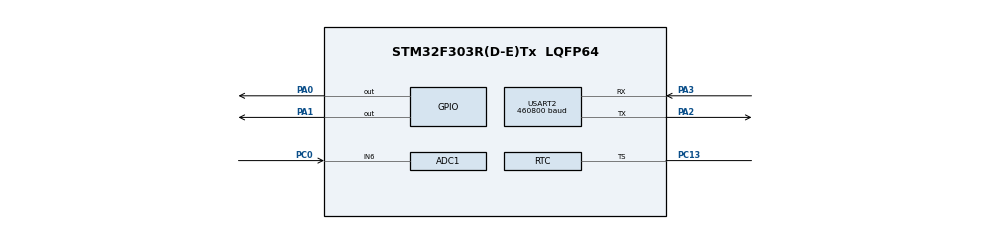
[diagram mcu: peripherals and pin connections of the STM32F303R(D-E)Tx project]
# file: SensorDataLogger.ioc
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ADC1.Channel-0\#ChannelRegularConversion=ADC_CHANNEL_6
ADC1.ClockPrescaler=ADC_CLOCK_SYNC_PCLK_DIV1
ADC1.NbrOfConversionFlag=1
ADC1.Offset-0\#ChannelRegularConversion=0
ADC1.OffsetNumber-0\#ChannelRegularConversion=ADC_OFFSET_NONE
ADC1.Rank-0\#ChannelRegularConversion=1
ADC1.SamplingTime-0\#ChannelRegularConversion=ADC_SAMPLETIME_1CYCLE_5
ADC1.master=1
FREERTOS.Tasks01=readDHT11Data,24,128,StartDefaultTask,Default,NULL,Dynamic,NULL,NULL;PotentiometerDa,24,128,readPotentiometerData,Default,NULL,Dynamic,NULL,NULL
Mcu.Family=STM32F3
Mcu.Name=STM32F303R(D-E)Tx
Mcu.Package=LQFP64
NVIC.PriorityGroup=NVIC_PRIORITYGROUP_4
NVIC.TIM1_UP_TIM16_IRQn=true\:0\:0\:false\:false\:true\:false\:false\:true
NVIC.TimeBase=TIM1_UP_TIM16_IRQn
NVIC.TimeBaseIP=TIM1
PA0.Signal=GPIO_Output
PA1.Signal=GPIO_Output
PA13.Mode=Serial_Wire
PA13.Signal=SYS_JTMS-SWDIO
PA14.Mode=Serial_Wire
PA14.Signal=SYS_JTCK-SWCLK
PA2.Mode=Asynchronous
PA2.Signal=USART2_TX
PA3.Mode=Asynchronous
PA3.Signal=USART2_RX
PC0.Signal=ADCx_IN6
PC13.Mode=Timestamp enabled
PC13.Signal=RTC_TS
PF0-OSC_IN.Mode=HSE-External-Oscillator
PF0-OSC_IN.Signal=RCC_OSC_IN
PF1-OSC_OUT.Mode=HSE-External-Oscillator
PF1-OSC_OUT.Signal=RCC_OSC_OUT
ProjectManager.HeapSize=0x200
ProjectManager.StackSize=0x400
ProjectManager.TargetToolchain=STM32CubeIDE
RCC.AHBFreq_Value=72000000
RCC.APB1CLKDivider=RCC_HCLK_DIV2
RCC.APB1Freq_Value=36000000
RCC.APB1TimFreq_Value=72000000
RCC.APB2Freq_Value=72000000
RCC.APB2TimFreq_Value=72000000
RCC.CortexFreq_Value=72000000
RCC.HCLKFreq_Value=72000000
RCC.HSE_VALUE=8000000
RCC.HSI_VALUE=8000000
RCC.LSE_VALUE=32768
RCC.PLLMUL=RCC_PLL_MUL9
RCC.PLLSourceVirtual=RCC_PLLSOURCE_HSE
RCC.SYSCLKFreq_VALUE=72000000
RCC.SYSCLKSourceVirtual=RCC_SYSCLKSOURCE_PLLCLK
RCC.USBFreq_Value=72000000
RCC.Usart1ClockSelection=RCC_USART1CLKSOURCE_SYSCLK
RTC.Date=28
RTC.WeekDay=RTC_WEEKDAY_WEDNESDAY
RTC.Year=20
SH.ADCx_IN6.0=ADC1_IN6,IN6-Single-Ended
TIM2.Period=0xFFFF-1
TIM2.Prescaler=72-1
USART2.BaudRate=460800
USART2.VirtualMode-Asynchronous=VM_ASYNC
VP_FREERTOS_VS_CMSIS_V2.Mode=CMSIS_V2
VP_RTC_VS_RTC_Activate.Mode=RTC_Enabled
VP_RTC_VS_RTC_Calendar.Mode=RTC_Calendar
VP_SYS_VS_tim1.Mode=TIM1
VP_TIM2_VS_ClockSourceINT.Mode=Internal
board=custom

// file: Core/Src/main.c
/* USER CODE BEGIN Header */
/**
  ******************************************************************************
  * @file           : main.c
  * @brief          : Main program body
  ******************************************************************************
  * @attention
  *
  * <h2><center>&copy; Copyright (c) 2020 STMicroelectronics.
  * All rights reserved.</center></h2>
  *
  * This software component is licensed by ST under BSD 3-Clause license,
  * the "License"; You may not use this file except in compliance with the
  * License. You may obtain a copy of the License at:
  *                        opensource.org/licenses/BSD-3-Clause
  *
  ******************************************************************************
  */
/* USER CODE END Header */

#include "main.h"
#include "cmsis_os.h"

/* USER CODE BEGIN Includes */
#include <string.h>
#include "data_logger.h"
#include "dht11_driver.h"
/* USER CODE END Includes */

/* USER CODE BEGIN PD */
#define MIN_STACK_SIZE configMINIMAL_STACK_SIZE
/* USER CODE END PD */

ADC_HandleTypeDef hadc1;

RTC_HandleTypeDef hrtc;

TIM_HandleTypeDef htim2;

UART_HandleTypeDef huart2;

/* Definitions for DHT11TaskHandle */
osThreadId_t DHT11TaskHandle;
const osThreadAttr_t DHT11Task_attributes = {
  .name = "DHT11Task",
  .priority = (osPriority_t) osPriorityNormal,
  .stack_size = MIN_STACK_SIZE * 4
};
/* Definitions for PotentiometerTaskHandle */
osThreadId_t PotentiometerTaskHandle;
const osThreadAttr_t PotentiometerTask_attributes = {
  .name = "PotentiometerTask",
  .priority = (osPriority_t) osPriorityNormal,
  .stack_size = MIN_STACK_SIZE * 3
};

static void SystemClock_Config(void);
static void MX_GPIO_Init(void);
static void MX_TIM2_Init(void);
static void MX_USART2_UART_Init(void);
static void MX_ADC1_Init(void);
static void MX_RTC_Init(void);
void readDHT11Data(void *argument);
void readPotentiometerData(void *argument);

/* USER CODE BEGIN PFP */
uint32_t used_mem(uint32_t address);

uint32_t flash_erase(uint32_t address);
uint32_t flash_copy_page(uint32_t src, uint32_t dst);
uint8_t define_page(uint32_t address);

/* USER CODE END PFP */

/* USER CODE BEGIN 0 */

void set_time (void)
{
  RTC_TimeTypeDef sTime;
  RTC_DateTypeDef sDate;
  char chTime[8] = {0}, chDate[11] = {0},
	   chHours[2] = {0}, chMinutes[2] = {0}, chSeconds[2] = {0};
  memcpy(chTime, __TIME__, 8);
  memcpy(chDate, __DATE__, 11);
  memcpy(chHours, chTime, 2);
  memcpy(chMinutes, chTime+3, 2);
  memcpy(chSeconds, chTime+6, 2);

  sTime.Hours = (atoi(chHours) > 12) ? atoi(chHours) - 12 : atoi(chHours); // set hours
  sTime.Minutes = atoi(chMinutes); // set minutes
  sTime.Seconds = atoi(chSeconds); // set seconds
  sTime.DayLightSaving = RTC_DAYLIGHTSAVING_NONE;
  sTime.StoreOperation = RTC_STOREOPERATION_RESET;
  if (HAL_RTC_SetTime(&hrtc, &sTime, RTC_FORMAT_BCD) != HAL_OK)
  {
    //_Error_Handler(__FILE__, __LINE__);
	  return;
  }
  sDate.WeekDay = RTC_WEEKDAY_TUESDAY; //  day
  sDate.Month = RTC_MONTH_MAY; // month
  sDate.Date = 0x5; // date
  sDate.Year = 0x16; // year
  if (HAL_RTC_SetDate(&hrtc, &sDate, RTC_FORMAT_BCD) != HAL_OK)
  {
    //_Error_Handler(__FILE__, __LINE__);
	  return;
  }
  HAL_RTCEx_BKUPWrite(&hrtc, RTC_BKP_DR1, 0x32F2); // backup register
}

void get_time(volatile char* time)
{
	//char time[10] = {0};
	//char date[10] = {0};
 RTC_DateTypeDef gDate;
 RTC_TimeTypeDef gTime;
/* Get the RTC current Time */
 HAL_RTC_GetTime(&hrtc, &gTime, RTC_FORMAT_BIN);
/* Get the RTC current Date */
 HAL_RTC_GetDate(&hrtc, &gDate, RTC_FORMAT_BIN);
/* Display time Format: hh:mm:ss */
// memcpy(time, &gTime.Hours, 2);
// memcpy(time + 2, &(":"), 1);
// memcpy(time, &gTime.Minutes, 2);
// memcpy(time + 2, &(":"), 1);
// memcpy(time, &gTime.Seconds, 2);
 sprintf((char*)time,"%02d:%02d:%02d",gTime.Hours, gTime.Minutes, gTime.Seconds);
 int len = strlen(time);
 len = sizeof(time);
/* Display date Format: dd-mm-yy */
 //sprintf((char*)date,"%02d-%02d-%2d",gDate.Date, gDate.Month, 2000 + gDate.Year);
}

uint32_t g_TicksToDelay = 0;
uint8_t u8Presence = 0;

uint8_t PendST = 0;
int32_t  OS_Tick_Enable (void) {
  if (PendST != 0U) {
    PendST = 0U;
    SCB->ICSR = SCB_ICSR_PENDSTSET_Msk;
  }
  SysTick->CTRL |=  SysTick_CTRL_ENABLE_Msk;
  return (0);
}

int32_t  OS_Tick_Disable (void) {
  SysTick->CTRL &= ~SysTick_CTRL_ENABLE_Msk;
  if ((SCB->ICSR & SCB_ICSR_PENDSTSET_Msk) != 0U) {
    SCB->ICSR = SCB_ICSR_PENDSTCLR_Msk;
    PendST = 1U;
  }
  return (0);
}

/* USER CODE END 0 */

int main(void)
{

  /* MCU Configuration--------------------------------------------------------*/

  /* Reset of all peripherals, Initializes the Flash interface and the Systick. */
  HAL_Init();

  /* Configure the system clock */
  SystemClock_Config();

  /* Initialize all configured peripherals */
  MX_GPIO_Init();
  MX_TIM2_Init();
  MX_USART2_UART_Init();
  MX_ADC1_Init();
  MX_RTC_Init();
  /* USER CODE BEGIN 2 */
  HAL_TIM_Base_Start(&htim2);
  DHT11_SetTimer(&htim2);

  DATA_LOG_S TestTmp_S = {0}, TestHmd_S = {0};
  DATA_LOG_S TestHeaders_S = {0};
  memcpy(TestTmp_S.bBuffer, LOGS_BEGIN, sizeof(DATA_LOG_S));
  memcpy(TestHmd_S.bBuffer, LOGS_BEGIN+16, sizeof(DATA_LOG_S));
  memcpy(TestHeaders_S.bBuffer, LOGGER_DATA, sizeof(DATA_LOG_S));
  FlashErase(FLASH_STORAGE);
  FlashErase(MIRROR_PAGE);
  LoggerInit();
  set_time();
  HAL_GPIO_WritePin(GPIOA, GPIO_PIN_0, SET);
//  HAL_HAL_FLASH_Unlock(); HAL_FLASH_OB_Unlock();
//  uint32_t test = 0;
//  for(int i = 0; i < 10; ++i)
//	  test = (*((__IO uint8_t*)(LOGGER_DATA + i))) = i;
//  HAL_HAL_FLASH_Lock(); HAL_FLASH_OB_Lock();

  //NVIC_SetPriorityGrouping( NVIC_PriorityGroup_4 );
  /* USER CODE END 2 */

  /* Init scheduler */
  osKernelInitialize();

  /* creation of DHT11TaskHandle */
  DHT11TaskHandle = osThreadNew(readDHT11Data, NULL, &DHT11Task_attributes);

  /* creation of PotentiometerTaskHandle */
  PotentiometerTaskHandle = osThreadNew(readPotentiometerData, NULL, &PotentiometerTask_attributes);

  /* Start scheduler */
  osKernelStart();

  /* We should never get here as control is now taken by the scheduler */
  /* Infinite loop */
  while (1)
  {

  }
}

void SystemClock_Config(void)
{
  RCC_OscInitTypeDef RCC_OscInitStruct = {0};
  RCC_ClkInitTypeDef RCC_ClkInitStruct = {0};
  RCC_PeriphCLKInitTypeDef PeriphClkInit = {0};

  /** Initializes the CPU, AHB and APB busses clocks
  */
  RCC_OscInitStruct.OscillatorType = RCC_OSCILLATORTYPE_HSI|RCC_OSCILLATORTYPE_LSI;
  RCC_OscInitStruct.HSIState = RCC_HSI_ON;
  RCC_OscInitStruct.HSICalibrationValue = RCC_HSICALIBRATION_DEFAULT;
  RCC_OscInitStruct.LSIState = RCC_LSI_ON;
  RCC_OscInitStruct.PLL.PLLState = RCC_PLL_ON;
  RCC_OscInitStruct.PLL.PLLSource = RCC_PLLSOURCE_HSI;
  RCC_OscInitStruct.PLL.PLLMUL = RCC_PLL_MUL2;
  RCC_OscInitStruct.PLL.PREDIV = RCC_PREDIV_DIV1;
  if (HAL_RCC_OscConfig(&RCC_OscInitStruct) != HAL_OK)
  {
    Error_Handler();
  }
  /** Initializes the CPU, AHB and APB busses clocks
  */
  RCC_ClkInitStruct.ClockType = RCC_CLOCKTYPE_HCLK|RCC_CLOCKTYPE_SYSCLK
                              |RCC_CLOCKTYPE_PCLK1|RCC_CLOCKTYPE_PCLK2;
  RCC_ClkInitStruct.SYSCLKSource = RCC_SYSCLKSOURCE_PLLCLK;
  RCC_ClkInitStruct.AHBCLKDivider = RCC_SYSCLK_DIV1;
  RCC_ClkInitStruct.APB1CLKDivider = RCC_HCLK_DIV2;
  RCC_ClkInitStruct.APB2CLKDivider = RCC_HCLK_DIV1;

  if (HAL_RCC_ClockConfig(&RCC_ClkInitStruct, FLASH_LATENCY_0) != HAL_OK)
  {
    Error_Handler();
  }
  PeriphClkInit.PeriphClockSelection = RCC_PERIPHCLK_USART2|RCC_PERIPHCLK_RTC
                              |RCC_PERIPHCLK_TIM2;
  PeriphClkInit.Usart2ClockSelection = RCC_USART2CLKSOURCE_PCLK1;
  PeriphClkInit.RTCClockSelection = RCC_RTCCLKSOURCE_LSI;
  PeriphClkInit.Tim2ClockSelection = RCC_TIM2CLK_HCLK;
  if (HAL_RCCEx_PeriphCLKConfig(&PeriphClkInit) != HAL_OK)
  {
    Error_Handler();
  }
}

static void MX_ADC1_Init(void)
{

  ADC_MultiModeTypeDef multimode = {0};
  ADC_ChannelConfTypeDef sConfig = {0};

  /** Common config
  */
  hadc1.Instance = ADC1;
  hadc1.Init.ClockPrescaler = ADC_CLOCK_SYNC_PCLK_DIV1;
  hadc1.Init.Resolution = ADC_RESOLUTION_12B;
  hadc1.Init.ScanConvMode = ADC_SCAN_DISABLE;
  hadc1.Init.ContinuousConvMode = DISABLE;
  hadc1.Init.DiscontinuousConvMode = DISABLE;
  hadc1.Init.ExternalTrigConvEdge = ADC_EXTERNALTRIGCONVEDGE_NONE;
  hadc1.Init.ExternalTrigConv = ADC_SOFTWARE_START;
  hadc1.Init.DataAlign = ADC_DATAALIGN_RIGHT;
  hadc1.Init.NbrOfConversion = 1;
  hadc1.Init.DMAContinuousRequests = DISABLE;
  hadc1.Init.EOCSelection = ADC_EOC_SINGLE_CONV;
  hadc1.Init.LowPowerAutoWait = DISABLE;
  hadc1.Init.Overrun = ADC_OVR_DATA_OVERWRITTEN;
  if (HAL_ADC_Init(&hadc1) != HAL_OK)
  {
    Error_Handler();
  }
  /** Configure the ADC multi-mode
  */
  multimode.Mode = ADC_MODE_INDEPENDENT;
  if (HAL_ADCEx_MultiModeConfigChannel(&hadc1, &multimode) != HAL_OK)
  {
    Error_Handler();
  }
  /** Configure Regular Channel
  */
  sConfig.Channel = ADC_CHANNEL_6;
  sConfig.Rank = ADC_REGULAR_RANK_1;
  sConfig.SingleDiff = ADC_SINGLE_ENDED;
  sConfig.SamplingTime = ADC_SAMPLETIME_1CYCLE_5;
  sConfig.OffsetNumber = ADC_OFFSET_NONE;
  sConfig.Offset = 0;
  if (HAL_ADC_ConfigChannel(&hadc1, &sConfig) != HAL_OK)
  {
    Error_Handler();
  }

}

static void MX_RTC_Init(void)
{

  RTC_TimeTypeDef sTime = {0};
  RTC_DateTypeDef sDate = {0};

  /** Initialize RTC Only
  */
  hrtc.Instance = RTC;
  hrtc.Init.HourFormat = RTC_HOURFORMAT_24;
  hrtc.Init.AsynchPrediv = 127;
  hrtc.Init.SynchPrediv = 255;
  hrtc.Init.OutPut = RTC_OUTPUT_DISABLE;
  hrtc.Init.OutPutPolarity = RTC_OUTPUT_POLARITY_HIGH;
  hrtc.Init.OutPutType = RTC_OUTPUT_TYPE_OPENDRAIN;
  if (HAL_RTC_Init(&hrtc) != HAL_OK)
  {
    Error_Handler();
  }

  /** Initialize RTC and set the Time and Date
  */
  sTime.Hours = 0x0;
  sTime.Minutes = 0x0;
  sTime.Seconds = 0x0;
  sTime.DayLightSaving = RTC_DAYLIGHTSAVING_NONE;
  sTime.StoreOperation = RTC_STOREOPERATION_RESET;
  if (HAL_RTC_SetTime(&hrtc, &sTime, RTC_FORMAT_BCD) != HAL_OK)
  {
    Error_Handler();
  }
  sDate.WeekDay = RTC_WEEKDAY_WEDNESDAY;
  sDate.Month = RTC_MONTH_JANUARY;
  sDate.Date = 0x28;
  sDate.Year = 0x20;

  if (HAL_RTC_SetDate(&hrtc, &sDate, RTC_FORMAT_BCD) != HAL_OK)
  {
    Error_Handler();
  }
  /** Enable the TimeStamp
  */
  if (HAL_RTCEx_SetTimeStamp(&hrtc, RTC_TIMESTAMPEDGE_RISING, RTC_TIMESTAMPPIN_DEFAULT) != HAL_OK)
  {
    Error_Handler();
  }

}

static void MX_TIM2_Init(void)
{

  TIM_ClockConfigTypeDef sClockSourceConfig = {0};
  TIM_MasterConfigTypeDef sMasterConfig = {0};

  htim2.Instance = TIM2;
  htim2.Init.Prescaler = 16-1;
  htim2.Init.CounterMode = TIM_COUNTERMODE_UP;
  htim2.Init.Period = 0xFFFF-1;
  htim2.Init.ClockDivision = TIM_CLOCKDIVISION_DIV1;
  htim2.Init.AutoReloadPreload = TIM_AUTORELOAD_PRELOAD_DISABLE;
  if (HAL_TIM_Base_Init(&htim2) != HAL_OK)
  {
    Error_Handler();
  }
  sClockSourceConfig.ClockSource = TIM_CLOCKSOURCE_INTERNAL;
  if (HAL_TIM_ConfigClockSource(&htim2, &sClockSourceConfig) != HAL_OK)
  {
    Error_Handler();
  }
  sMasterConfig.MasterOutputTrigger = TIM_TRGO_RESET;
  sMasterConfig.MasterSlaveMode = TIM_MASTERSLAVEMODE_DISABLE;
  if (HAL_TIMEx_MasterConfigSynchronization(&htim2, &sMasterConfig) != HAL_OK)
  {
    Error_Handler();
  }

}

static void MX_USART2_UART_Init(void)
{

  huart2.Instance = USART2;
  huart2.Init.BaudRate = 460800;
  huart2.Init.WordLength = UART_WORDLENGTH_8B;
  huart2.Init.StopBits = UART_STOPBITS_1;
  huart2.Init.Parity = UART_PARITY_NONE;
  huart2.Init.Mode = UART_MODE_TX_RX;
  huart2.Init.HwFlowCtl = UART_HWCONTROL_NONE;
  huart2.Init.OverSampling = UART_OVERSAMPLING_16;
  huart2.Init.OneBitSampling = UART_ONE_BIT_SAMPLE_DISABLE;
  huart2.AdvancedInit.AdvFeatureInit = UART_ADVFEATURE_NO_INIT;
  if (HAL_UART_Init(&huart2) != HAL_OK)
  {
    Error_Handler();
  }

}

static void MX_GPIO_Init(void)
{
  GPIO_InitTypeDef GPIO_InitStruct = {0};

  /* GPIO Ports Clock Enable */
  __HAL_RCC_GPIOC_CLK_ENABLE();
  __HAL_RCC_GPIOF_CLK_ENABLE();
  __HAL_RCC_GPIOA_CLK_ENABLE();

  /*Configure GPIO pin Output Level */
  HAL_GPIO_WritePin(GPIOA, GPIO_PIN_0|GPIO_PIN_1, GPIO_PIN_RESET);

  /*Configure GPIO pins : PA0 PA1 */
  GPIO_InitStruct.Pin = GPIO_PIN_0|GPIO_PIN_1;
  GPIO_InitStruct.Mode = GPIO_MODE_OUTPUT_PP;
  GPIO_InitStruct.Pull = GPIO_NOPULL;
  GPIO_InitStruct.Speed = GPIO_SPEED_FREQ_LOW;
  HAL_GPIO_Init(GPIOA, &GPIO_InitStruct);

}

/* USER CODE BEGIN Header_readDHT11Data */
void readDHT11Data(void *argument)
{
  /* USER CODE BEGIN 5 */
#ifdef DEBUG
	char chMsg[30] = {0};
    char chData[5] = {0};
#endif
    const DHT11_DATA_S *pDHT11Data = 0;
	DATA_LOG_S TemperatureData_S = {0},
			   HumidityData_S = {0};
	static uint8_t Dht11PrevValues[4] = {0};
#ifdef DEBUG
	DATA_LOG_S Test_S = {0};
#endif

	TemperatureData_S.DATA_S.DataTypeE = TMP;
	HumidityData_S.DATA_S.DataTypeE = HMD;
	TickType_t xLastWakeTime;
  /* Infinite loop */
  for(;;)
  {
#ifdef DEBUG
	  memset(chMsg, 0, 30);
	  memset(chData, 0, 5);
#endif
	  OS_Tick_Disable();
	  /* start communicating with sensor */
	  DHT11_Start();
	  u8Presence = DHT11_CheckResponse();
	  /* try again if synchronization failed */
	  if(1 != u8Presence)
	  {
		  continue;
	  }
	  else
	  {
		  ;
	  }
	  /* read humidity & temperature */
	  pDHT11Data = DHT11_ReadData();
	  /* check control sum */
	  if(0 == DHT11_IsDataValid())
	  {
		  continue;
	  }
	  else
	  {
		  ;
	  }
	  OS_Tick_Enable();

	  TemperatureData_S.DATA_S.DataTypeE = TMP;
	  HumidityData_S.DATA_S.DataTypeE = HMD;

	  get_time(HumidityData_S.DATA_S.sTimestamp);
	  get_time(TemperatureData_S.DATA_S.sTimestamp);

	  HumidityData_S.DATA_S.bDataBuffer[0] = pDHT11Data->u8Humidity;
	  HumidityData_S.DATA_S.bDataBuffer[1] = pDHT11Data->u8HmdFloatPart;
	  TemperatureData_S.DATA_S.bDataBuffer[0] = pDHT11Data->u8Temperature;
	  TemperatureData_S.DATA_S.bDataBuffer[1] = pDHT11Data->u8TmpFloatPart;

	  if((Dht11PrevValues[0] != HumidityData_S.bBuffer[1])
			  ||
		 (Dht11PrevValues[1] != HumidityData_S.bBuffer[2]))
	  {
		  LoggerSaveData(HumidityData_S.bBuffer, sizeof(DATA_LOG_S));
		  Dht11PrevValues[0] = HumidityData_S.bBuffer[1];
		  Dht11PrevValues[1] = HumidityData_S.bBuffer[2];
	  }
	  else
	  {
		  /* skip this value */
	  }

	  if((Dht11PrevValues[2] != TemperatureData_S.bBuffer[1])
			  ||
		 (Dht11PrevValues[3] != TemperatureData_S.bBuffer[2]))
	  {
		  LoggerSaveData(TemperatureData_S.bBuffer, sizeof(DATA_LOG_S));
		  Dht11PrevValues[2] = TemperatureData_S.bBuffer[1];
		  Dht11PrevValues[3] = TemperatureData_S.bBuffer[2];
	  }
	  else
	  {
		  /* skip this value */
	  }

	  // Initialise the xLastWakeTime variable with the current time.
	  xLastWakeTime = xTaskGetTickCount();

	  LoggerSaveState(UPDATED);
	  LOGGER_DATA_S TestHeaders_S = {0};
	  memcpy(&TestHeaders_S, LOGGER_DATA, 16);

	  memset(HumidityData_S.DATA_S.bDataBuffer, 0, sizeof(uint32_t)+8);
	  memset(TemperatureData_S.DATA_S.bDataBuffer, 0, sizeof(uint32_t)+8);
//	  u8Presence = 0;
//	  memset(chMsg, 0, 20);
//	  uint64_t f = 0.0;
#ifdef DEBUG
	  uint16_t u16CheckSum = 0;
	  memcpy(chData, pDHT11Data, sizeof(DHT11_DATA_S));
	  for(int i = 0; i<4; ++i)
	  {
//	  	uint8_t value = chData[i];
//	  	uint8_t f_part = chData[i+1];
	  	u16CheckSum += chData[i];
//	  	u16CheckSum += chData[i+1];
//	  	sprintf(chMsg, "Data%d: %d,%d\n\r", i, value, f_part);
//	  	HAL_UART_Transmit(&huart2, chMsg, strlen(chMsg), HAL_MAX_DELAY);
	  }
	  sprintf(chMsg, "Humidity: %d,%d\n\r", pDHT11Data->u8Humidity, pDHT11Data->u8HmdFloatPart);
	  HAL_UART_Transmit(&huart2, chMsg, strlen(chMsg), HAL_MAX_DELAY);
	  sprintf(chMsg, "Temperature: %d,%d\n\r", pDHT11Data->u8Temperature, pDHT11Data->u8TmpFloatPart);
	  HAL_UART_Transmit(&huart2, chMsg, strlen(chMsg), HAL_MAX_DELAY);
	  //HAL_UART_Transmit(&huart2, TemperatureData_S.DATA_S.sTimestamp, 8, HAL_MAX_DELAY);
	  sprintf(chMsg, "CHECK_SUM: %d\n\r", ((uint8_t*)&u16CheckSum)[0]);
	  HAL_UART_Transmit(&huart2, chMsg, strlen(chMsg), HAL_MAX_DELAY);
#endif
	  //vTaskDelayUntil( &xLastWakeTime, 8500);
	  //vTaskDelay(g_TicksToDelay*1000/portTICK_PERIOD_MS);
	  HAL_Delay(5000);
  }
  /* USER CODE END 5 */
}

/* USER CODE BEGIN Header_readPotentiometerData */
void readPotentiometerData(void *argument)
{
#ifdef DEBUG
	char chMsg[10] = {0};
#endif
	uint32_t uiValue = 0;
	DATA_LOG_S PotentiometerData_S = {0};
	TickType_t xLastWakeTime;
	PotentiometerData_S.DATA_S.DataTypeE = PTM;
  /* Infinite loop */
  for(;;)
  {
#ifdef DEBUG
	  memset(chMsg, 0, 10);
#endif
	  HAL_ADC_Start(&hadc1);
	  HAL_ADC_PollForConversion(&hadc1, HAL_MAX_DELAY);
	  uiValue = HAL_ADC_GetValue(&hadc1);
	  memcpy(PotentiometerData_S.DATA_S.bDataBuffer,
	  		(char*)(&uiValue),
	  		sizeof(uint16_t));

	  OS_Tick_Disable();
	  LoggerSaveData(PotentiometerData_S.bBuffer, sizeof(DATA_LOG_S));
	  OS_Tick_Enable();
#ifdef DEBUG
	  sprintf(chMsg, "PTM: %u\n\r", uiValue);
	  HAL_UART_Transmit(&huart2, chMsg, strlen(chMsg), HAL_MAX_DELAY);
#endif
	  g_TicksToDelay = uiValue/1000+1;
	  //vTaskDelay(g_TicksToDelay);
	  HAL_Delay(2000);
	  //HAL_Delay(g_TicksToDelay*1000);
    //osDelay(500);
  }
  /* USER CODE END readPotentiometerData */
}

 /**
  * @brief  Period elapsed callback in non blocking mode
  * @note   This function is called  when TIM1 interrupt took place, inside
  * HAL_TIM_IRQHandler(). It makes a direct call to HAL_IncTick() to increment
  * a global variable "uwTick" used as application time base.
  * @param  htim : TIM handle
  * @retval None
  */
void HAL_TIM_PeriodElapsedCallback(TIM_HandleTypeDef *htim)
{
  if (htim->Instance == TIM1) {
    HAL_IncTick();
  }
}

void Error_Handler(void)
{
}

/************************ (C) COPYRIGHT STMicroelectronics *****END OF FILE****/
